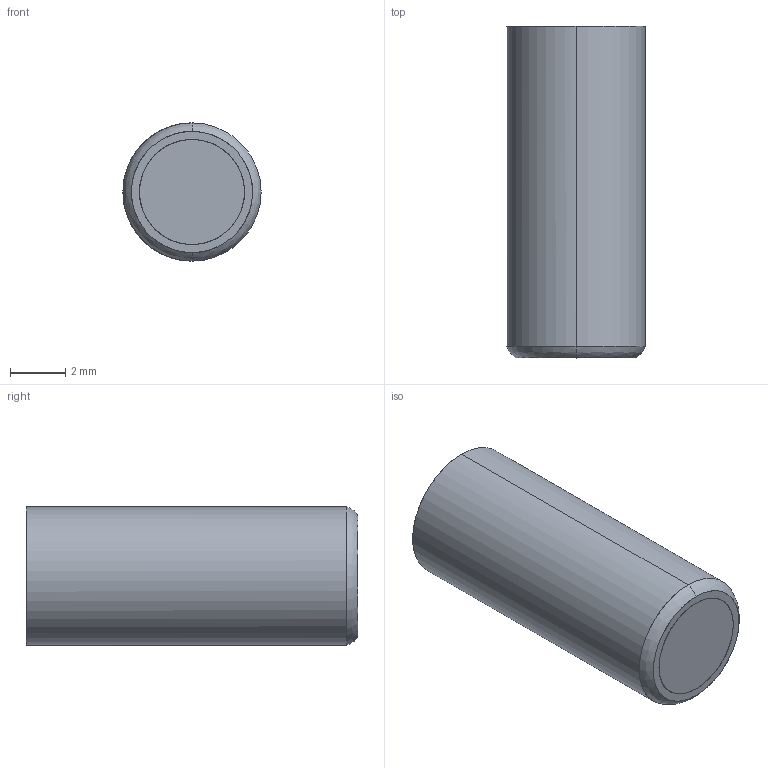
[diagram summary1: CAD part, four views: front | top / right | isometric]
IGES file: header records copied from the file, then geometry measured from it (millimetres).
Start section: START RECORD GO HERE.
Global section: file name: fa053000.igs; native system: DASSAULT SYSTEMES CATIA V5 R20 - www.3ds.com; preprocessor: CATIA Version 5 Release 20 ; author: Utente; organization: NB04-ASUS; date: 20201108.083956; units: millimetre
Bounding box: 5 x 12 x 5 mm (x, y, z)
Surface area: 596.6 mm2 (no closed solid volume)
Topology: 0 solids, 0 shells, 257 faces, 1042 edges, 1040 vertices
Faces by surface type: bspline 180, revolution 48, plane 29
